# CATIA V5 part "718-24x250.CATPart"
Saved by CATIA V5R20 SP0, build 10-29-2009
Part number: 718-24x250
Definition: NONE
Nomenclature: 718-24x250
Source: Unknown
Description: 718-24x250
Bounding box of the stored display mesh (mm): x 0 to 280, y -16 to 16, z -16 to 16
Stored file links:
  C:\Users\Utente\Desktop\IO LAVORO\3D X SITO CF\X SITO\718\718-24x250.CATPart

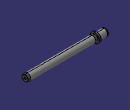
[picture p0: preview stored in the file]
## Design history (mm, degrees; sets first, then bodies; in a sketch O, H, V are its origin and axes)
Body1 "718-24x250" (main body)
  Solid1: solid without history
